One B-rep face of a CAD part: STEP entity #1379.
In plain terms, the planar face has unit normal (-1, 0, 0).
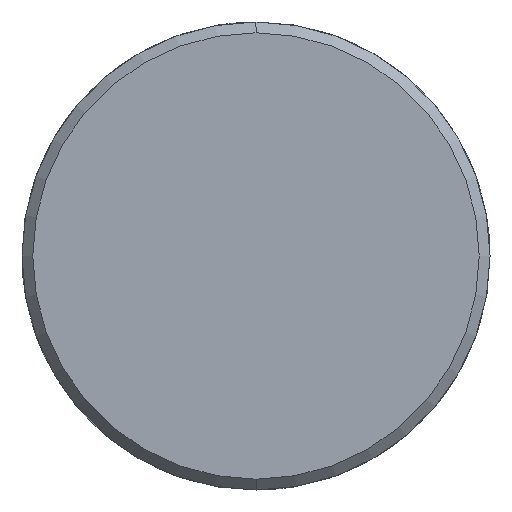
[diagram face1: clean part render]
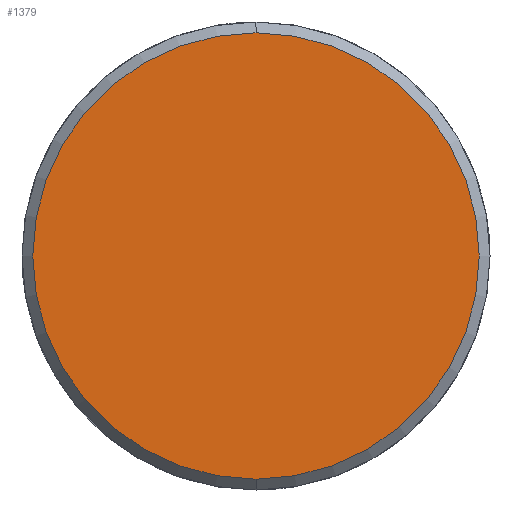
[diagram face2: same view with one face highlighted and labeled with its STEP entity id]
Its self-contained STEP definition (entity closure, numbers rounded to 3 decimals):
#1311=CARTESIAN_POINT('Vertex',(-10.,0.,-31.)) ;
#1314=CARTESIAN_POINT('Axis2P3D Location',(-10.,0.,0.)) ;
#1318=CARTESIAN_POINT('Vertex',(-10.,31.,0.)) ;
#1321=CARTESIAN_POINT('Axis2P3D Location',(-10.,0.,0.)) ;
#1325=CARTESIAN_POINT('Vertex',(-10.,0.,31.)) ;
#1347=CARTESIAN_POINT('Axis2P3D Location',(-10.,0.,0.)) ;
#1351=CARTESIAN_POINT('Vertex',(-10.,-31.,0.)) ;
#1354=CARTESIAN_POINT('Axis2P3D Location',(-10.,0.,0.)) ;
#1368=CARTESIAN_POINT('Axis2P3D Location',(-10.,0.,0.)) ;
#1315=DIRECTION('Axis2P3D Direction',(1.,0.,-0.)) ;
#1322=DIRECTION('Axis2P3D Direction',(1.,0.,-0.)) ;
#1348=DIRECTION('Axis2P3D Direction',(1.,0.,-0.)) ;
#1355=DIRECTION('Axis2P3D Direction',(1.,0.,-0.)) ;
#1369=DIRECTION('Axis2P3D Direction',(1.,0.,-0.)) ;
#1370=DIRECTION('Axis2P3D XDirection',(-0.,0.,-1.)) ;
#1316=AXIS2_PLACEMENT_3D('Circle Axis2P3D',#1314,#1315,$) ;
#1323=AXIS2_PLACEMENT_3D('Circle Axis2P3D',#1321,#1322,$) ;
#1349=AXIS2_PLACEMENT_3D('Circle Axis2P3D',#1347,#1348,$) ;
#1356=AXIS2_PLACEMENT_3D('Circle Axis2P3D',#1354,#1355,$) ;
#1371=AXIS2_PLACEMENT_3D('Plane Axis2P3D',#1368,#1369,#1370) ;
#1374=ORIENTED_EDGE('',*,*,#1320,.F.) ;
#1375=ORIENTED_EDGE('',*,*,#1358,.F.) ;
#1376=ORIENTED_EDGE('',*,*,#1353,.F.) ;
#1377=ORIENTED_EDGE('',*,*,#1327,.F.) ;
#1379=ADVANCED_FACE('351-50X96X300',(#1378),#1372,.F.) ;
#1317=CIRCLE('generated circle',#1316,31.) ;
#1324=CIRCLE('generated circle',#1323,31.) ;
#1350=CIRCLE('generated circle',#1349,31.) ;
#1357=CIRCLE('generated circle',#1356,31.) ;
#1320=EDGE_CURVE('',#1312,#1319,#1317,.T.) ;
#1327=EDGE_CURVE('',#1319,#1326,#1324,.T.) ;
#1353=EDGE_CURVE('',#1326,#1352,#1350,.T.) ;
#1358=EDGE_CURVE('',#1352,#1312,#1357,.T.) ;
#1373=EDGE_LOOP('',(#1374,#1375,#1376,#1377)) ;
#1378=FACE_OUTER_BOUND('',#1373,.T.) ;
#1372=PLANE('Plane',#1371) ;
#1312=VERTEX_POINT('',#1311) ;
#1319=VERTEX_POINT('',#1318) ;
#1326=VERTEX_POINT('',#1325) ;
#1352=VERTEX_POINT('',#1351) ;
